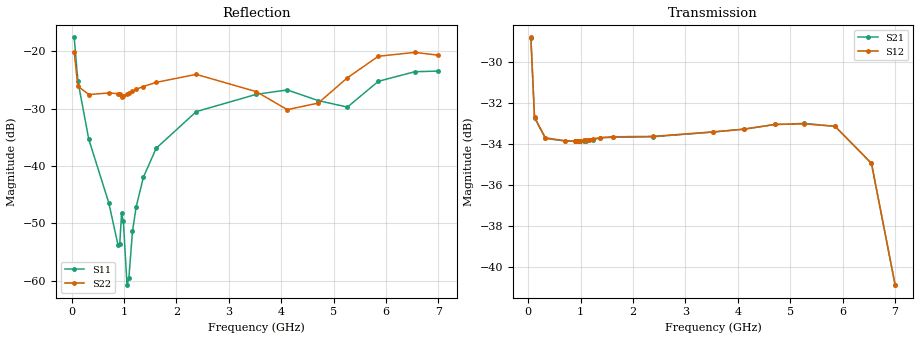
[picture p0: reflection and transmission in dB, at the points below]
! Integrated Device Technology
! Corporate Headquarters
! 6024 Silver Creek Valley Road
! San Jose, CA 95138  USA
! Phone:  1-408-284-8200
! Toll Free:  1-800-223-1366
! Webpage:  http://www.idt.com/
! Timing and RF Division
! 515 Groton Road, Suite 102
! Westford, MA 01886-6024
! Device:  F2258
! Description: Voltage Variable RF Attenuator
! Frequency:  50.0 -  6000.00 MHz
! Package:  3x3 mm Thin QFN Plastic Package: 16 pin
! Ports:  2 RF, 2 DC
!  Pin  1  = NC
!  Pin  2  = NC
!  Pin  3  = RF2  = Port 2
!  Pin  4  = GND
!  Pin  5  = Vdd
!  Pin  6  = NC
!  Pin  7  = VCTRL
!  Pin  8  = NC
!  Pin  9  = GND
!  Pin 10  = RF1  = Port 1
!  Pin 11  = NC
!  Pin 12  = NC
!  Pin 13  = NC
!  Pin 14  = NC
!  Pin 15  = NC
!  Pin 16  = NC
! Vcntrl:  1.830 Volts
! Vdd:  +3.300 Volts
! Current:  1.155 mA
! Data:  The device was measured on a the F2258 evaluation board which has
!  individual transmission lines to the RF pins.  Data was collected
!  using a calibrated network analyzer.  The evaluation board was
!  de-embedded using a TRL calibration technique.
!  The reference plane is the edge of the package pin.
! Misc:  SN 10
!  Action Tracker AT0285
! Date Measured:  2014-12-10
! Date:  2016-01-13  MJV
! Note:
!  Integrated Device Technology supplies this data as a sample of measured
!  data at the package pin for this product.  Your particular data for this
!  product may vary.
!  Data was taken at 25 degrees C.
!  Integrated Device Technology reserves the right to change this data at anytime.
!Freq_(GHz)  S11M_(dB)  S11P_(deg)  S21M_(dB)  S21P_(deg)  S12M_(dB)  S12P_(deg)  S22M_(dB)  S22P_(deg)
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# GHz S dB R 50
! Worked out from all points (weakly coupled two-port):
!   201 points, 50 MHz to 7 GHz, reference 50 ohm
!   highest |S21| = -28.81 dB at 50 MHz (marker M1); lowest = -40.9 dB at 7 GHz (marker M2)
!   lowest |S11| = -60.8 dB at 1.058 GHz (marker M3), VSWR 1.00, Z = 49.9 + j0.0458 ohm
!   |S11| at or under -10 dB: start of sweep to end of sweep
!   |S22| runs from -30.7 to -19.7 dB; largest |S21 - S12| = 8.4e-05
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0.05  -17.54 -110.7  -28.81 -62.1  -28.80 -62.0  -20.13 -96.1
0.1195  -25.12 -106.4  -32.72 -32.9  -32.70 -32.8  -26.03 -53.4
0.328  -35.31 -113.6  -33.73 -14.3  -33.70 -14.3  -27.51 -18.1
0.71025  -46.42 -132.8  -33.86 -9.6  -33.85 -9.6  -27.24 -5.1
0.884  -53.69 167.0  -33.87 -9.3  -33.86 -9.3  -27.36 -5.0
0.91875  -53.67 147.9  -33.87 -9.3  -33.86 -9.3  -27.36 -5.1
0.9535  -48.25 -159.3  -33.87 -9.2  -33.86 -9.2  -27.91 -2.2
0.98825  -49.63 -170.6  -33.87 -9.2  -33.84 -9.2  -27.81 -3.1
1.05775  -60.76 150.0  -33.86 -9.2  -33.83 -9.2  -27.39 -2.7
1.0925  -59.60 105.2  -33.84 -9.2  -33.82 -9.2  -27.30 -2.8
1.162  -51.39 61.6  -33.81 -9.3  -33.80 -9.4  -26.96 -2.7
1.2315  -47.13 41.5  -33.79 -9.5  -33.76 -9.5  -26.60 -2.9
1.3705  -41.93 34.7  -33.71 -10.2  -33.69 -10.2  -26.11 -2.6
1.61375  -36.89 31.4  -33.67 -11.7  -33.65 -11.7  -25.39 -3.4
2.37825  -30.50 47.3  -33.65 -16.1  -33.63 -16.1  -23.99 -2.6
3.525  -27.47 91.2  -33.42 -23.7  -33.41 -23.7  -27.01 6.1
4.11575  -26.71 104.8  -33.28 -28.1  -33.28 -28.1  -30.15 4.6
4.7065  -28.57 95.3  -33.05 -33.4  -33.05 -33.4  -29.00 -10.9
5.2625  -29.70 53.8  -33.00 -39.6  -33.02 -39.5  -24.59 -25.4
5.85325  -25.20 29.5  -33.14 -49.6  -33.14 -49.5  -20.83 -30.6
6.54825  -23.53 44.8  -34.94 -67.9  -34.95 -68.0  -20.16 -59.1
7  -23.42 84.3  -40.87 -65.0  -40.89 -64.8  -20.65 -123.9
